VERSION 5.8 ;
BUSBITCHARS "[]" ;
DIVIDERCHAR "/" ;
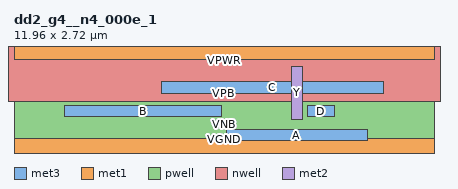
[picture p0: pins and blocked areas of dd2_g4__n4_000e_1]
MACRO dd2_g4__n4_000e_1
  CLASS CORE ;
  ORIGIN 0 0 ;
  SIZE 11.960 BY 2.720 ;
  SYMMETRY X Y ;
  SITE unithd ;
  PIN A
    DIRECTION INPUT ;
    USE SIGNAL ;
    ANTENNAGATEAREA 0.213000 ;
    PORT
      LAYER met3 ;
        RECT 6.045 0.175 10.055 0.505 ;
    END
  END A
  PIN B
    DIRECTION INPUT ;
    USE SIGNAL ;
    ANTENNAGATEAREA 0.213000 ;
    PORT
      LAYER met3 ;
        RECT 1.445 0.855 5.915 1.185 ;
    END
  END B
  PIN C
    DIRECTION INPUT ;
    USE SIGNAL ;
    ANTENNAGATEAREA 0.213000 ;
    PORT
      LAYER met3 ;
        RECT 4.205 1.535 10.515 1.865 ;
    END
  END C
  PIN D
    DIRECTION INPUT ;
    USE SIGNAL ;
    ANTENNAGATEAREA 0.213000 ;
    PORT
      LAYER met3 ;
        RECT 8.345 0.855 9.135 1.185 ;
    END
  END D
  PIN VGND
    DIRECTION INOUT ;
    USE GROUND ;
    SHAPE ABUTMENT ;
    PORT
      LAYER met1 ;
        RECT 0.000 -0.240 11.960 0.240 ;
    END
  END VGND
  PIN VNB
    DIRECTION INOUT ;
    USE GROUND ;
    PORT
      LAYER pwell ;
        RECT 0.000 0.000 11.960 1.305 ;
    END
  END VNB
  PIN VPB
    DIRECTION INOUT ;
    USE POWER ;
    PORT
      LAYER nwell ;
        RECT -0.190 1.305 12.150 2.910 ;
    END
  END VPB
  PIN VPWR
    DIRECTION INOUT ;
    USE POWER ;
    SHAPE ABUTMENT ;
    PORT
      LAYER met1 ;
        RECT 0.000 2.480 11.960 2.960 ;
    END
  END VPWR
  PIN Y
    DIRECTION OUTPUT ;
    USE SIGNAL ;
    ANTENNADIFFAREA 2.115600 ;
    PORT
      LAYER met2 ;
        RECT 7.890 0.790 8.210 2.305 ;
    END
  END Y
  OBS
    LAYER li1 ;
      RECT 0.000 -0.085 11.960 0.085 ;
      RECT 0.605 0.085 0.775 0.565 ;
      RECT 4.745 0.085 4.915 0.565 ;
      RECT 8.885 0.085 9.055 0.565 ;
      RECT 3.285 0.255 3.615 0.710 ;
      RECT 6.505 0.255 6.835 0.710 ;
      RECT 7.425 0.255 7.755 0.710 ;
      RECT 10.645 0.255 10.975 0.710 ;
      RECT 1.065 0.380 1.235 1.075 ;
      RECT 0.945 1.075 1.275 1.245 ;
      RECT 2.445 0.380 2.615 1.075 ;
      RECT 2.325 1.075 2.655 1.245 ;
      RECT 4.285 0.380 4.455 1.075 ;
      RECT 4.165 1.075 4.495 1.245 ;
      RECT 5.665 0.380 5.835 1.075 ;
      RECT 5.545 1.075 5.875 1.245 ;
      RECT 8.425 0.380 8.595 1.075 ;
      RECT 8.305 1.075 8.635 1.245 ;
      RECT 9.805 0.380 9.975 1.075 ;
      RECT 9.685 1.075 10.015 1.245 ;
      RECT 1.485 1.075 1.815 1.245 ;
      RECT 1.525 1.245 1.695 2.340 ;
      RECT 2.865 1.075 3.195 1.245 ;
      RECT 2.905 1.245 3.075 2.340 ;
      RECT 4.705 1.075 5.035 1.245 ;
      RECT 4.745 1.245 4.915 2.340 ;
      RECT 6.085 1.075 6.415 1.245 ;
      RECT 6.125 1.245 6.295 2.340 ;
      RECT 8.845 1.075 9.175 1.245 ;
      RECT 8.885 1.245 9.055 2.340 ;
      RECT 10.225 1.075 10.555 1.245 ;
      RECT 10.265 1.245 10.435 2.340 ;
      RECT 0.525 1.505 0.855 2.465 ;
      RECT 3.745 1.505 4.075 2.465 ;
      RECT 6.965 1.505 7.295 2.465 ;
      RECT 7.885 1.505 8.215 2.465 ;
      RECT 11.105 1.505 11.435 2.465 ;
      RECT 1.985 1.495 2.155 2.635 ;
      RECT 5.205 1.495 5.375 2.635 ;
      RECT 0.000 2.635 11.960 2.805 ;
    LAYER met1 ;
      RECT 1.005 0.380 1.295 0.710 ;
      RECT 2.385 0.380 2.675 0.710 ;
      RECT 4.225 0.380 4.515 0.710 ;
      RECT 5.605 0.380 5.895 0.710 ;
      RECT 6.505 0.380 6.835 0.710 ;
      RECT 8.365 0.380 8.655 0.710 ;
      RECT 9.745 0.380 10.035 0.710 ;
      RECT 10.645 0.380 10.975 0.710 ;
      RECT 3.285 0.380 3.615 0.710 ;
      RECT 7.425 0.380 7.755 0.710 ;
      RECT 3.290 0.710 3.610 0.850 ;
      RECT 7.430 0.710 7.750 0.850 ;
      RECT 7.890 0.790 8.210 0.850 ;
      RECT 3.285 0.850 8.215 0.990 ;
      RECT 3.290 0.990 3.610 1.050 ;
      RECT 7.430 0.990 7.750 1.050 ;
      RECT 7.890 0.990 8.210 1.050 ;
      RECT 2.370 1.230 2.690 1.290 ;
      RECT 2.830 1.230 3.150 1.290 ;
      RECT 6.970 1.230 7.290 1.290 ;
      RECT 10.650 1.230 10.970 1.290 ;
      RECT 2.365 1.290 10.975 1.430 ;
      RECT 2.370 1.430 2.690 1.490 ;
      RECT 2.830 1.430 3.150 1.490 ;
      RECT 6.970 1.430 7.290 1.490 ;
      RECT 10.650 1.430 10.970 1.490 ;
      RECT 1.465 2.010 1.755 2.340 ;
      RECT 2.845 2.010 3.135 2.340 ;
      RECT 3.745 2.010 4.075 2.340 ;
      RECT 0.530 1.670 0.850 1.730 ;
      RECT 0.990 1.670 1.310 1.730 ;
      RECT 4.670 1.670 4.990 1.730 ;
      RECT 6.510 1.670 6.830 1.730 ;
      RECT 0.525 1.730 6.835 1.870 ;
      RECT 0.990 1.870 1.310 1.930 ;
      RECT 4.670 1.870 4.990 1.930 ;
      RECT 6.510 1.870 6.830 1.930 ;
      RECT 0.530 1.870 0.850 2.010 ;
      RECT 4.675 1.930 4.985 2.175 ;
      RECT 0.525 2.010 0.855 2.340 ;
      RECT 4.685 2.175 4.975 2.340 ;
      RECT 6.065 2.010 6.355 2.340 ;
      RECT 6.965 2.010 7.295 2.340 ;
      RECT 7.885 2.010 8.215 2.340 ;
      RECT 8.825 2.010 9.115 2.340 ;
      RECT 10.205 2.010 10.495 2.340 ;
      RECT 11.105 2.010 11.435 2.340 ;
    LAYER met2 ;
      RECT 9.750 0.155 10.030 0.210 ;
      RECT 9.730 0.210 10.050 0.675 ;
      RECT 3.290 0.415 3.610 1.050 ;
      RECT 7.430 0.415 7.750 1.050 ;
      RECT 5.590 0.415 5.910 1.150 ;
      RECT 5.610 1.150 5.890 1.205 ;
      RECT 8.350 0.415 8.670 1.150 ;
      RECT 8.370 1.150 8.650 1.205 ;
      RECT 2.370 0.415 2.690 1.490 ;
      RECT 10.650 0.415 10.970 1.490 ;
      RECT 4.210 0.415 4.530 1.830 ;
      RECT 4.230 1.830 4.510 1.885 ;
      RECT 0.990 0.415 1.310 1.930 ;
      RECT 6.510 0.415 6.830 1.930 ;
      RECT 0.530 1.670 0.850 2.305 ;
      RECT 1.470 0.835 1.750 0.890 ;
      RECT 1.450 0.890 1.770 2.305 ;
      RECT 2.830 1.230 3.150 2.305 ;
      RECT 4.670 1.670 4.990 2.305 ;
      RECT 6.070 0.155 6.350 0.210 ;
      RECT 6.050 0.210 6.370 2.305 ;
      RECT 6.970 1.230 7.290 2.305 ;
      RECT 8.830 0.835 9.110 0.890 ;
      RECT 8.810 0.890 9.130 2.305 ;
      RECT 10.210 1.515 10.490 1.570 ;
      RECT 10.190 1.570 10.510 2.305 ;
      RECT 3.750 2.045 4.070 2.510 ;
      RECT 3.770 2.510 4.050 2.565 ;
      RECT 11.110 2.045 11.430 2.510 ;
      RECT 11.130 2.510 11.410 2.565 ;
    LAYER met3 ;
      RECT 3.745 2.215 11.435 2.545 ;
  END
END dd2_g4__n4_000e_1
END LIBRARY
